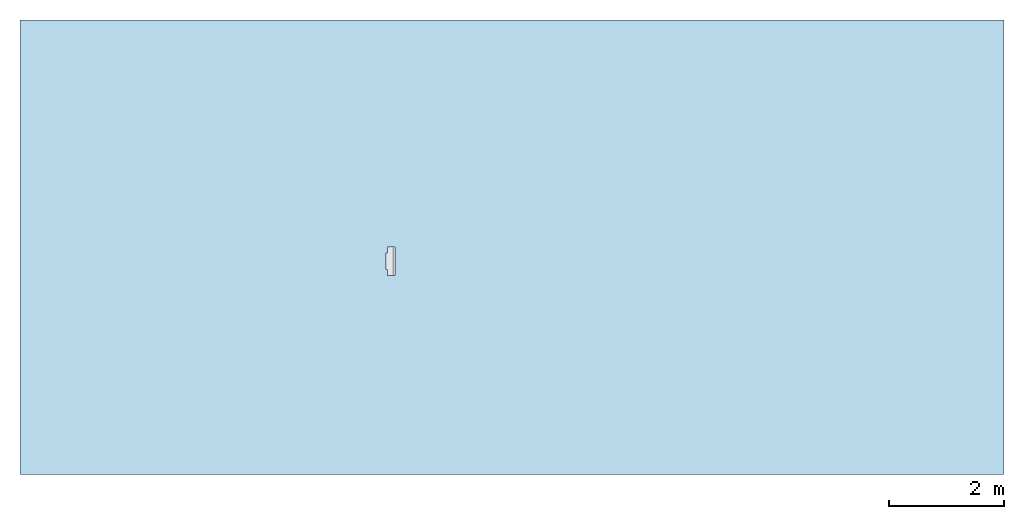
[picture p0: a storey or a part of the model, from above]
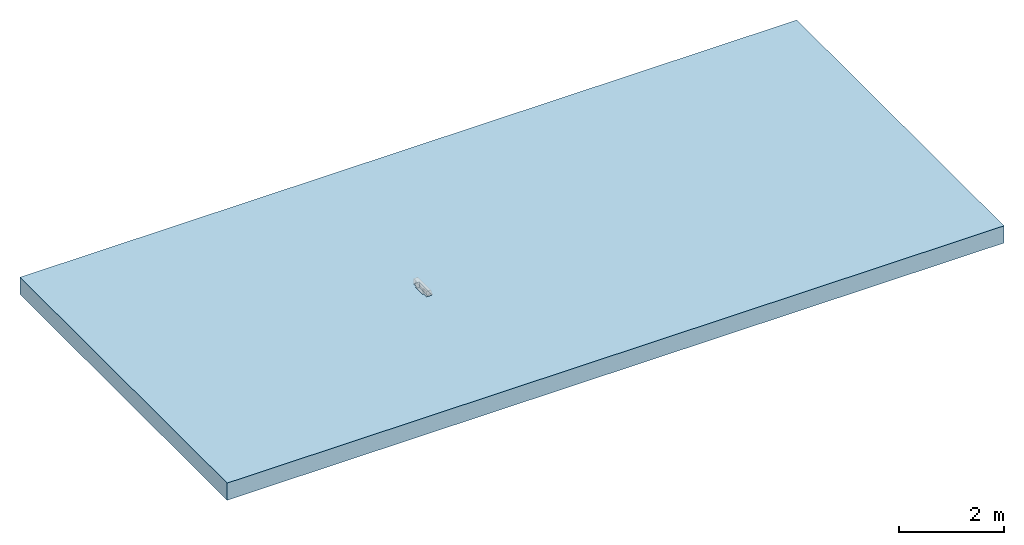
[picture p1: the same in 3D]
Properties of the parts of a building model (IFC2X3)

# File
Description: ViewDefinition [CoordinationView]
File name: 7949 - Access Unit - 500mm LG.ifc
Time: 2013-08-30T17:37:04
Written by: Autodesk Revit 2013
Made in: 20120221_2030(x64)

# IfcProject, Project Number
LongName: Project Name; Phase: Project Status

# IfcSite, Default
RefLatitude: 42, 21, 30, 344238; RefLongitude: -71, -3, -35, -194702; RefElevation: 0 mm

# IfcBuilding
Pset_BuildingCommon - NumberOfStoreys: 1
Other - Project Number: Project Number; Client Name: Owner; Project Issue Date: Issue Date; Project Name: Project Name; Project Address: ## Street City, State Zip; Project Status: Project Status

# IfcBuildingStorey, Level 1
LongName: Level 1; Elevation: 0 mm
Constraints - Elevation Base: 0; Elevation: 0 mm
Graphics - Line Weight: 1; Line Pattern: Center; Color: 0; Symbol at End 2 Default: yes; Symbol at End 1 Default: no; Symbol: M_Level Head - Circle: M_Level Head - Circle
Identity Data - Name: Level 1; Structural: no; Building Story: yes
Dimensions - Computation Height: 0 mm

# IfcBuildingElementProxy: 7949 - Access Unit - 500mm LG, Civil-Drainage-Channel-ACO-KerbDrain-HB255:7949 - Access Unit - 500mm LG:7949 - Access Unit - 500mm LG:736856
In: Level 1
Material: Iron, Cast, ACO Polymer Concrete.
Other - CreatedBy: www.aco.co.uk; Revision: 1
Constraints - Level: Level: Level 1; Moves With Nearby Elements: no
Dimensions - Volume: 11380136 mm3; LH Void Start: -2000 mm; RH Void Start: -2000 mm; Void Width: 125 mm; Void Length: 500 mm; Void Start: 0 mm; Void Depth: -130 mm; LH Void End: -2005 mm; Access Depth: 255 mm; RH Hole End: -2005 mm
Phasing - Phase Created: New Construction
Pset_BuildingElementProxyCommon - Reference: 7949 - Access Unit - 500mm LG
Data - Drainage Slot Intake area: N/A; Channel C.S.A: 0.01m²; Product Weight: 23.3 Kg; Concrete Surround Volume - Load Class A 15 - D 400 - Grass or Asphalt Pavement: 0.11m³/m; ACO Hydraulic Design Software: http://www.acodesign.co.uk; Load Class: A 15 - D 400; Installation - Concrete Grade: Refer to brochure; Product Dimensions: 500mm x 125/150mm x 255mm (LxWxH); Invert Depth: 235mm; Drainage Slot Width: N/A; Concrete Surround Volume - Load Class A 15 - D 400 - Concrete Pavement: 0.12m³/m; Product Standard: BS EN 1433:2002, CE marked, Kitemarked; Connection Pipe O.D: N/A; Hydraulic Performance: http://www.aco.co.uk/download.php?id=120
Construction - RH drop kerb: no; HB255 - 500: no; LH drop kerb: no; HB255 - 1000: no; Access Unit: yes; Closing end cap: no; Centre Stone: no
Identity Data - Assembly Code: D2040; Model: ACO KerbDrain HB255; e-mail Technical: technical@aco.co.uk; Address: ACO Business Park, Hitchin Road, Shefford, Bedfordshire, United Kingdom SG17 5TE; Maintenance guidelines: http://www.aco.co.uk/download.php?id=120; URL: www.aco.co.uk; Product Code: 7949; Assembly Description: Rain Water Drainage; Installation guidelines: http://www.aco.co.uk/download.php?id=120; Type Comments: ACO KerbDrain HB255 half battered rodding access unit 500mm long; OmniClass Number: 23.70.50.24; e-mail Sales: customersupport@aco.co.uk; Cost: 0; Fax: +44 (0)1462 815895; OmniClass Title: Rainwater Removal; Product Page URL: http://www.aco.co.uk/product_detail.php?id=3; Price: POA - contact ACO; Manufacturer: ACO Technologies plc - ACO Water Management Division; Telephone: +44 (0)1462 816666; Model Description: Combined kerb and drainage system; Product brochure: http://www.aco.co.uk/download.php?id=120
Materials and Finishes - Access Cover/Frame Colour: Black; End Cap Colour: N/A; Access Cover/Frame Finish: Water Based Paint Coating; End Cap Material: N/A; Access Cover/Frame Material: Ductile Iron; Channel Colour: Grey; Channel Material: Vienite® Synthetic Resin Concrete
Green Building Properties - Access Cover/Frame Recycled Material Content: Between 40% - 90%; End Cap Recycled Material Content: N/A; End Cap Recyclable: N/A; Channel Recyclable: Fully recyclable; Channel Recycled Material Content: 20% minimum; Access Cover/Frame Recyclable: Fully recyclable
General - TagNumber: 0.000000; SerialNumber: 0.000000

# IfcOpeningElement: Recess (2)
In: Level 1
Structural - Enable Analytical Model: no; Structural: no
Constraints - Level: Level: Level 1; Height Offset From Level: 0 mm; Room Bounding: yes; Related to Mass: no
Dimensions - Volume: 54026943759 mm3; Perimeter: 50000 mm; Thickness: 400 mm; Area: 135090000 mm2
Phasing - Phase Created: New Construction
Materials and Finishes - Structural Material: Plant
Construction - Function: 0; Default Thickness: 400 mm
Analytical Properties - Absorptance: 0.1; Roughness: 1
Graphics - Coarse Scale Fill Color: 0

# IfcSlab: Floor:Generic Floor - 400mm, Floor:Generic Floor - 400mm:193825
In: Level 1
PredefinedType: FLOOR; Material: Plant 400 mm
Structural - Enable Analytical Model: no; Structural: no
Constraints - Level: Level: Level 1; Height Offset From Level: 0 mm; Room Bounding: yes; Related to Mass: no
Dimensions - Volume: 54026943759 mm3; Perimeter: 50000 mm; Thickness: 400 mm; Area: 135090000 mm2
Phasing - Phase Created: New Construction
Pset_SlabCommon - Reference: Generic Floor - 400mm; IsExternal: no; LoadBearing: yes
Materials and Finishes - Structural Material: Plant
Construction - Function: 0; Default Thickness: 400 mm
Analytical Properties - Absorptance: 0.1; Roughness: 1
Graphics - Coarse Scale Fill Color: 0
